VERSION 5.8 ;
BUSBITCHARS "[]" ;
DIVIDERCHAR "/" ;

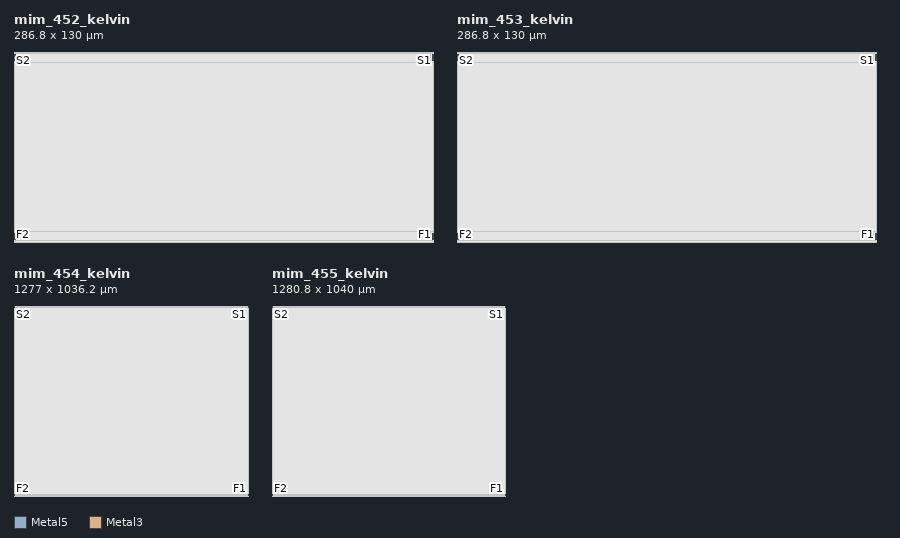
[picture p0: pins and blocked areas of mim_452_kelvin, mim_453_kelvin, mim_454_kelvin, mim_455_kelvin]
MACRO mim_452_kelvin
  CLASS BLOCK ;
  ORIGIN 0 0 ;
  SIZE 286.800 BY 130.000 ;
  SYMMETRY X Y ;
  PIN F1
    DIRECTION INOUT ;
    USE SIGNAL ;
    PORT
      LAYER Metal5 ;
      RECT 286.000 2.000 286.800 6.000 ;
    END
  END F1
  PIN S1
    DIRECTION INOUT ;
    USE SIGNAL ;
    PORT
      LAYER Metal5 ;
      RECT 286.000 124.000 286.800 128.000 ;
    END
  END S1
  PIN F2
    DIRECTION INOUT ;
    USE SIGNAL ;
    PORT
      LAYER Metal3 ;
      RECT 0.000 2.000 0.800 6.000 ;
    END
  END F2
  PIN S2
    DIRECTION INOUT ;
    USE SIGNAL ;
    PORT
      LAYER Metal3 ;
      RECT 0.000 124.000 0.800 128.000 ;
    END
  END S2
  OBS
    LAYER Metal1 ;
    RECT 0.000 0.000 286.800 130.000 ;
    LAYER Via1 ;
    RECT 0.000 0.000 286.800 130.000 ;
    LAYER Metal2 ;
    RECT 0.000 0.000 286.800 130.000 ;
    LAYER Via2 ;
    RECT 0.000 0.000 286.800 130.000 ;
    LAYER Metal3 ;
    RECT 0.000 0.000 286.800 1.000 ;
    RECT 1.800 1.000 286.800 7.000 ;
    RECT 0.000 7.000 286.800 123.000 ;
    RECT 1.800 123.000 286.800 129.000 ;
    RECT 0.000 129.000 286.800 130.000 ;
    LAYER Via3 ;
    RECT 0.000 0.000 286.800 130.000 ;
    LAYER Metal4 ;
    RECT 0.000 0.000 286.800 130.000 ;
    LAYER Via4 ;
    RECT 0.000 0.000 286.800 130.000 ;
    LAYER Metal5 ;
    RECT 0.000 0.000 286.800 1.000 ;
    RECT 0.000 1.000 285.000 7.000 ;
    RECT 0.000 7.000 286.800 123.000 ;
    RECT 0.000 123.000 285.000 129.000 ;
    RECT 0.000 129.000 286.800 130.000 ;
  END
END mim_452_kelvin

MACRO mim_453_kelvin
  CLASS BLOCK ;
  ORIGIN 0 0 ;
  SIZE 286.800 BY 130.000 ;
  SYMMETRY X Y ;
  PIN F1
    DIRECTION INOUT ;
    USE SIGNAL ;
    PORT
      LAYER Metal5 ;
      RECT 286.000 2.000 286.800 6.000 ;
    END
  END F1
  PIN S1
    DIRECTION INOUT ;
    USE SIGNAL ;
    PORT
      LAYER Metal5 ;
      RECT 286.000 124.000 286.800 128.000 ;
    END
  END S1
  PIN F2
    DIRECTION INOUT ;
    USE SIGNAL ;
    PORT
      LAYER Metal3 ;
      RECT 0.000 2.000 0.800 6.000 ;
    END
  END F2
  PIN S2
    DIRECTION INOUT ;
    USE SIGNAL ;
    PORT
      LAYER Metal3 ;
      RECT 0.000 124.000 0.800 128.000 ;
    END
  END S2
  OBS
    LAYER Metal1 ;
    RECT 0.000 0.000 286.800 130.000 ;
    LAYER Via1 ;
    RECT 0.000 0.000 286.800 130.000 ;
    LAYER Metal2 ;
    RECT 0.000 0.000 286.800 130.000 ;
    LAYER Via2 ;
    RECT 0.000 0.000 286.800 130.000 ;
    LAYER Metal3 ;
    RECT 0.000 0.000 286.800 1.000 ;
    RECT 1.800 1.000 286.800 7.000 ;
    RECT 0.000 7.000 286.800 123.000 ;
    RECT 1.800 123.000 286.800 129.000 ;
    RECT 0.000 129.000 286.800 130.000 ;
    LAYER Via3 ;
    RECT 0.000 0.000 286.800 130.000 ;
    LAYER Metal4 ;
    RECT 0.000 0.000 286.800 130.000 ;
    LAYER Via4 ;
    RECT 0.000 0.000 286.800 130.000 ;
    LAYER Metal5 ;
    RECT 0.000 0.000 286.800 1.000 ;
    RECT 0.000 1.000 285.000 7.000 ;
    RECT 0.000 7.000 286.800 123.000 ;
    RECT 0.000 123.000 285.000 129.000 ;
    RECT 0.000 129.000 286.800 130.000 ;
  END
END mim_453_kelvin

MACRO mim_454_kelvin
  CLASS BLOCK ;
  ORIGIN 0 0 ;
  SIZE 1277.000 BY 1036.200 ;
  SYMMETRY X Y ;
  PIN F1
    DIRECTION INOUT ;
    USE SIGNAL ;
    PORT
      LAYER Metal5 ;
      RECT 1276.200 2.000 1277.000 6.000 ;
    END
  END F1
  PIN S1
    DIRECTION INOUT ;
    USE SIGNAL ;
    PORT
      LAYER Metal5 ;
      RECT 1276.200 1030.200 1277.000 1034.200 ;
    END
  END S1
  PIN F2
    DIRECTION INOUT ;
    USE SIGNAL ;
    PORT
      LAYER Metal3 ;
      RECT 0.000 2.000 0.800 6.000 ;
    END
  END F2
  PIN S2
    DIRECTION INOUT ;
    USE SIGNAL ;
    PORT
      LAYER Metal3 ;
      RECT 0.000 1030.200 0.800 1034.200 ;
    END
  END S2
  OBS
    LAYER Metal1 ;
    RECT 0.000 0.000 1277.000 1036.200 ;
    LAYER Via1 ;
    RECT 0.000 0.000 1277.000 1036.200 ;
    LAYER Metal2 ;
    RECT 0.000 0.000 1277.000 1036.200 ;
    LAYER Via2 ;
    RECT 0.000 0.000 1277.000 1036.200 ;
    LAYER Metal3 ;
    RECT 0.000 0.000 1277.000 1.000 ;
    RECT 1.800 1.000 1277.000 7.000 ;
    RECT 0.000 7.000 1277.000 1029.200 ;
    RECT 1.800 1029.200 1277.000 1035.200 ;
    RECT 0.000 1035.200 1277.000 1036.200 ;
    LAYER Via3 ;
    RECT 0.000 0.000 1277.000 1036.200 ;
    LAYER Metal4 ;
    RECT 0.000 0.000 1277.000 1036.200 ;
    LAYER Via4 ;
    RECT 0.000 0.000 1277.000 1036.200 ;
    LAYER Metal5 ;
    RECT 0.000 0.000 1277.000 1.000 ;
    RECT 0.000 1.000 1275.200 7.000 ;
    RECT 0.000 7.000 1277.000 1029.200 ;
    RECT 0.000 1029.200 1275.200 1035.200 ;
    RECT 0.000 1035.200 1277.000 1036.200 ;
  END
END mim_454_kelvin

MACRO mim_455_kelvin
  CLASS BLOCK ;
  ORIGIN 0 0 ;
  SIZE 1280.800 BY 1040.000 ;
  SYMMETRY X Y ;
  PIN F1
    DIRECTION INOUT ;
    USE SIGNAL ;
    PORT
      LAYER Metal5 ;
      RECT 1280.000 2.000 1280.800 6.000 ;
    END
  END F1
  PIN S1
    DIRECTION INOUT ;
    USE SIGNAL ;
    PORT
      LAYER Metal5 ;
      RECT 1280.000 1034.000 1280.800 1038.000 ;
    END
  END S1
  PIN F2
    DIRECTION INOUT ;
    USE SIGNAL ;
    PORT
      LAYER Metal3 ;
      RECT 0.000 2.000 0.800 6.000 ;
    END
  END F2
  PIN S2
    DIRECTION INOUT ;
    USE SIGNAL ;
    PORT
      LAYER Metal3 ;
      RECT 0.000 1034.000 0.800 1038.000 ;
    END
  END S2
  OBS
    LAYER Metal1 ;
    RECT 0.000 0.000 1280.800 1040.000 ;
    LAYER Via1 ;
    RECT 0.000 0.000 1280.800 1040.000 ;
    LAYER Metal2 ;
    RECT 0.000 0.000 1280.800 1040.000 ;
    LAYER Via2 ;
    RECT 0.000 0.000 1280.800 1040.000 ;
    LAYER Metal3 ;
    RECT 0.000 0.000 1280.800 1.000 ;
    RECT 1.800 1.000 1280.800 7.000 ;
    RECT 0.000 7.000 1280.800 1033.000 ;
    RECT 1.800 1033.000 1280.800 1039.000 ;
    RECT 0.000 1039.000 1280.800 1040.000 ;
    LAYER Via3 ;
    RECT 0.000 0.000 1280.800 1040.000 ;
    LAYER Metal4 ;
    RECT 0.000 0.000 1280.800 1040.000 ;
    LAYER Via4 ;
    RECT 0.000 0.000 1280.800 1040.000 ;
    LAYER Metal5 ;
    RECT 0.000 0.000 1280.800 1.000 ;
    RECT 0.000 1.000 1279.000 7.000 ;
    RECT 0.000 7.000 1280.800 1033.000 ;
    RECT 0.000 1033.000 1279.000 1039.000 ;
    RECT 0.000 1039.000 1280.800 1040.000 ;
  END
END mim_455_kelvin

END LIBRARY
